VERSION 5.8 ;
BUSBITCHARS "[]" ;
DIVIDERCHAR "/" ;
UNITS
    DATABASE MICRONS 1000 ;
END UNITS

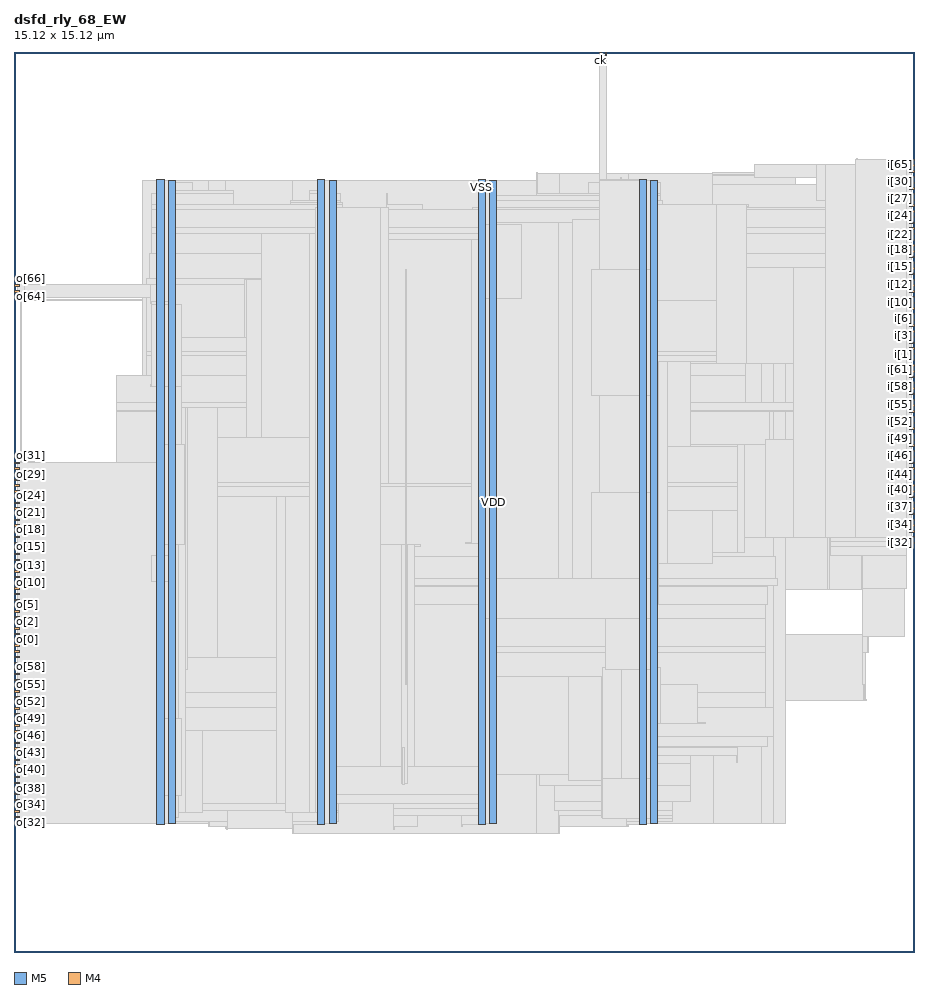
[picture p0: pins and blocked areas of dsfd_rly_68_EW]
MACRO dsfd_rly_68_EW
  FOREIGN dsfd_rly_68_EW 0 0 ;
  CLASS BLOCK ;
  SIZE 15.12 BY 15.12 ;
  PIN ck
    DIRECTION INPUT ;
    USE SIGNAL ;
    PORT
      LAYER M5 ;
        RECT  9.84 15.036 9.864 15.12 ;
    END
  END ck
  PIN i[0]
    DIRECTION INPUT ;
    USE SIGNAL ;
    PORT
      LAYER M4 ;
        RECT  15.036 9.936 15.12 9.96 ;
    END
  END i[0]
  PIN i[10]
    DIRECTION INPUT ;
    USE SIGNAL ;
    PORT
      LAYER M4 ;
        RECT  15.036 10.896 15.12 10.92 ;
    END
  END i[10]
  PIN i[11]
    DIRECTION INPUT ;
    USE SIGNAL ;
    PORT
      LAYER M4 ;
        RECT  15.036 10.992 15.12 11.016 ;
    END
  END i[11]
  PIN i[12]
    DIRECTION INPUT ;
    USE SIGNAL ;
    PORT
      LAYER M4 ;
        RECT  15.036 11.088 15.12 11.112 ;
    END
  END i[12]
  PIN i[13]
    DIRECTION INPUT ;
    USE SIGNAL ;
    PORT
      LAYER M4 ;
        RECT  15.036 11.184 15.12 11.208 ;
    END
  END i[13]
  PIN i[14]
    DIRECTION INPUT ;
    USE SIGNAL ;
    PORT
      LAYER M4 ;
        RECT  15.036 11.28 15.12 11.304 ;
    END
  END i[14]
  PIN i[15]
    DIRECTION INPUT ;
    USE SIGNAL ;
    PORT
      LAYER M4 ;
        RECT  15.036 11.376 15.12 11.4 ;
    END
  END i[15]
  PIN i[16]
    DIRECTION INPUT ;
    USE SIGNAL ;
    PORT
      LAYER M4 ;
        RECT  15.036 11.472 15.12 11.496 ;
    END
  END i[16]
  PIN i[17]
    DIRECTION INPUT ;
    USE SIGNAL ;
    PORT
      LAYER M4 ;
        RECT  15.036 11.568 15.12 11.592 ;
    END
  END i[17]
  PIN i[18]
    DIRECTION INPUT ;
    USE SIGNAL ;
    PORT
      LAYER M4 ;
        RECT  15.036 11.664 15.12 11.688 ;
    END
  END i[18]
  PIN i[19]
    DIRECTION INPUT ;
    USE SIGNAL ;
    PORT
      LAYER M4 ;
        RECT  15.036 11.76 15.12 11.784 ;
    END
  END i[19]
  PIN i[1]
    DIRECTION INPUT ;
    USE SIGNAL ;
    PORT
      LAYER M4 ;
        RECT  15.036 10.032 15.12 10.056 ;
    END
  END i[1]
  PIN i[20]
    DIRECTION INPUT ;
    USE SIGNAL ;
    PORT
      LAYER M4 ;
        RECT  15.036 11.856 15.12 11.88 ;
    END
  END i[20]
  PIN i[21]
    DIRECTION INPUT ;
    USE SIGNAL ;
    PORT
      LAYER M4 ;
        RECT  15.036 11.952 15.12 11.976 ;
    END
  END i[21]
  PIN i[22]
    DIRECTION INPUT ;
    USE SIGNAL ;
    PORT
      LAYER M4 ;
        RECT  15.036 12.048 15.12 12.072 ;
    END
  END i[22]
  PIN i[23]
    DIRECTION INPUT ;
    USE SIGNAL ;
    PORT
      LAYER M4 ;
        RECT  15.036 12.144 15.12 12.168 ;
    END
  END i[23]
  PIN i[24]
    DIRECTION INPUT ;
    USE SIGNAL ;
    PORT
      LAYER M4 ;
        RECT  15.036 12.24 15.12 12.264 ;
    END
  END i[24]
  PIN i[25]
    DIRECTION INPUT ;
    USE SIGNAL ;
    PORT
      LAYER M4 ;
        RECT  15.036 12.336 15.12 12.36 ;
    END
  END i[25]
  PIN i[26]
    DIRECTION INPUT ;
    USE SIGNAL ;
    PORT
      LAYER M4 ;
        RECT  15.036 12.432 15.12 12.456 ;
    END
  END i[26]
  PIN i[27]
    DIRECTION INPUT ;
    USE SIGNAL ;
    PORT
      LAYER M4 ;
        RECT  15.036 12.528 15.12 12.552 ;
    END
  END i[27]
  PIN i[28]
    DIRECTION INPUT ;
    USE SIGNAL ;
    PORT
      LAYER M4 ;
        RECT  15.036 12.624 15.12 12.648 ;
    END
  END i[28]
  PIN i[29]
    DIRECTION INPUT ;
    USE SIGNAL ;
    PORT
      LAYER M4 ;
        RECT  15.036 12.72 15.12 12.744 ;
    END
  END i[29]
  PIN i[2]
    DIRECTION INPUT ;
    USE SIGNAL ;
    PORT
      LAYER M4 ;
        RECT  15.036 10.128 15.12 10.152 ;
    END
  END i[2]
  PIN i[30]
    DIRECTION INPUT ;
    USE SIGNAL ;
    PORT
      LAYER M4 ;
        RECT  15.036 12.816 15.12 12.84 ;
    END
  END i[30]
  PIN i[31]
    DIRECTION INPUT ;
    USE SIGNAL ;
    PORT
      LAYER M4 ;
        RECT  15.036 12.912 15.12 12.936 ;
    END
  END i[31]
  PIN i[32]
    DIRECTION INPUT ;
    USE SIGNAL ;
    PORT
      LAYER M4 ;
        RECT  15.036 6.864 15.12 6.888 ;
    END
  END i[32]
  PIN i[33]
    DIRECTION INPUT ;
    USE SIGNAL ;
    PORT
      LAYER M4 ;
        RECT  15.036 6.96 15.12 6.984 ;
    END
  END i[33]
  PIN i[34]
    DIRECTION INPUT ;
    USE SIGNAL ;
    PORT
      LAYER M4 ;
        RECT  15.036 7.056 15.12 7.08 ;
    END
  END i[34]
  PIN i[35]
    DIRECTION INPUT ;
    USE SIGNAL ;
    PORT
      LAYER M4 ;
        RECT  15.036 7.152 15.12 7.176 ;
    END
  END i[35]
  PIN i[36]
    DIRECTION INPUT ;
    USE SIGNAL ;
    PORT
      LAYER M4 ;
        RECT  15.036 7.248 15.12 7.272 ;
    END
  END i[36]
  PIN i[37]
    DIRECTION INPUT ;
    USE SIGNAL ;
    PORT
      LAYER M4 ;
        RECT  15.036 7.344 15.12 7.368 ;
    END
  END i[37]
  PIN i[38]
    DIRECTION INPUT ;
    USE SIGNAL ;
    PORT
      LAYER M4 ;
        RECT  15.036 7.44 15.12 7.464 ;
    END
  END i[38]
  PIN i[39]
    DIRECTION INPUT ;
    USE SIGNAL ;
    PORT
      LAYER M4 ;
        RECT  15.036 7.536 15.12 7.56 ;
    END
  END i[39]
  PIN i[3]
    DIRECTION INPUT ;
    USE SIGNAL ;
    PORT
      LAYER M4 ;
        RECT  15.036 10.224 15.12 10.248 ;
    END
  END i[3]
  PIN i[40]
    DIRECTION INPUT ;
    USE SIGNAL ;
    PORT
      LAYER M4 ;
        RECT  15.036 7.632 15.12 7.656 ;
    END
  END i[40]
  PIN i[41]
    DIRECTION INPUT ;
    USE SIGNAL ;
    PORT
      LAYER M4 ;
        RECT  15.036 7.728 15.12 7.752 ;
    END
  END i[41]
  PIN i[42]
    DIRECTION INPUT ;
    USE SIGNAL ;
    PORT
      LAYER M4 ;
        RECT  15.036 7.824 15.12 7.848 ;
    END
  END i[42]
  PIN i[43]
    DIRECTION INPUT ;
    USE SIGNAL ;
    PORT
      LAYER M4 ;
        RECT  15.036 7.92 15.12 7.944 ;
    END
  END i[43]
  PIN i[44]
    DIRECTION INPUT ;
    USE SIGNAL ;
    PORT
      LAYER M4 ;
        RECT  15.036 8.016 15.12 8.04 ;
    END
  END i[44]
  PIN i[45]
    DIRECTION INPUT ;
    USE SIGNAL ;
    PORT
      LAYER M4 ;
        RECT  15.036 8.112 15.12 8.136 ;
    END
  END i[45]
  PIN i[46]
    DIRECTION INPUT ;
    USE SIGNAL ;
    PORT
      LAYER M4 ;
        RECT  15.036 8.208 15.12 8.232 ;
    END
  END i[46]
  PIN i[47]
    DIRECTION INPUT ;
    USE SIGNAL ;
    PORT
      LAYER M4 ;
        RECT  15.036 8.304 15.12 8.328 ;
    END
  END i[47]
  PIN i[48]
    DIRECTION INPUT ;
    USE SIGNAL ;
    PORT
      LAYER M4 ;
        RECT  15.036 8.4 15.12 8.424 ;
    END
  END i[48]
  PIN i[49]
    DIRECTION INPUT ;
    USE SIGNAL ;
    PORT
      LAYER M4 ;
        RECT  15.036 8.496 15.12 8.52 ;
    END
  END i[49]
  PIN i[4]
    DIRECTION INPUT ;
    USE SIGNAL ;
    PORT
      LAYER M4 ;
        RECT  15.036 10.32 15.12 10.344 ;
    END
  END i[4]
  PIN i[50]
    DIRECTION INPUT ;
    USE SIGNAL ;
    PORT
      LAYER M4 ;
        RECT  15.036 8.592 15.12 8.616 ;
    END
  END i[50]
  PIN i[51]
    DIRECTION INPUT ;
    USE SIGNAL ;
    PORT
      LAYER M4 ;
        RECT  15.036 8.688 15.12 8.712 ;
    END
  END i[51]
  PIN i[52]
    DIRECTION INPUT ;
    USE SIGNAL ;
    PORT
      LAYER M4 ;
        RECT  15.036 8.784 15.12 8.808 ;
    END
  END i[52]
  PIN i[53]
    DIRECTION INPUT ;
    USE SIGNAL ;
    PORT
      LAYER M4 ;
        RECT  15.036 8.88 15.12 8.904 ;
    END
  END i[53]
  PIN i[54]
    DIRECTION INPUT ;
    USE SIGNAL ;
    PORT
      LAYER M4 ;
        RECT  15.036 8.976 15.12 9 ;
    END
  END i[54]
  PIN i[55]
    DIRECTION INPUT ;
    USE SIGNAL ;
    PORT
      LAYER M4 ;
        RECT  15.036 9.072 15.12 9.096 ;
    END
  END i[55]
  PIN i[56]
    DIRECTION INPUT ;
    USE SIGNAL ;
    PORT
      LAYER M4 ;
        RECT  15.036 9.168 15.12 9.192 ;
    END
  END i[56]
  PIN i[57]
    DIRECTION INPUT ;
    USE SIGNAL ;
    PORT
      LAYER M4 ;
        RECT  15.036 9.264 15.12 9.288 ;
    END
  END i[57]
  PIN i[58]
    DIRECTION INPUT ;
    USE SIGNAL ;
    PORT
      LAYER M4 ;
        RECT  15.036 9.36 15.12 9.384 ;
    END
  END i[58]
  PIN i[59]
    DIRECTION INPUT ;
    USE SIGNAL ;
    PORT
      LAYER M4 ;
        RECT  15.036 9.456 15.12 9.48 ;
    END
  END i[59]
  PIN i[5]
    DIRECTION INPUT ;
    USE SIGNAL ;
    PORT
      LAYER M4 ;
        RECT  15.036 10.416 15.12 10.44 ;
    END
  END i[5]
  PIN i[60]
    DIRECTION INPUT ;
    USE SIGNAL ;
    PORT
      LAYER M4 ;
        RECT  15.036 9.552 15.12 9.576 ;
    END
  END i[60]
  PIN i[61]
    DIRECTION INPUT ;
    USE SIGNAL ;
    PORT
      LAYER M4 ;
        RECT  15.036 9.648 15.12 9.672 ;
    END
  END i[61]
  PIN i[62]
    DIRECTION INPUT ;
    USE SIGNAL ;
    PORT
      LAYER M4 ;
        RECT  15.036 9.744 15.12 9.768 ;
    END
  END i[62]
  PIN i[63]
    DIRECTION INPUT ;
    USE SIGNAL ;
    PORT
      LAYER M4 ;
        RECT  15.036 9.84 15.12 9.864 ;
    END
  END i[63]
  PIN i[64]
    DIRECTION INPUT ;
    USE SIGNAL ;
    PORT
      LAYER M4 ;
        RECT  15.036 13.008 15.12 13.032 ;
    END
  END i[64]
  PIN i[65]
    DIRECTION INPUT ;
    USE SIGNAL ;
    PORT
      LAYER M4 ;
        RECT  15.036 13.104 15.12 13.128 ;
    END
  END i[65]
  PIN i[66]
    DIRECTION INPUT ;
    USE SIGNAL ;
    PORT
      LAYER M4 ;
        RECT  15.036 13.2 15.12 13.224 ;
    END
  END i[66]
  PIN i[67]
    DIRECTION INPUT ;
    USE SIGNAL ;
    PORT
      LAYER M4 ;
        RECT  15.036 13.296 15.12 13.32 ;
    END
  END i[67]
  PIN i[6]
    DIRECTION INPUT ;
    USE SIGNAL ;
    PORT
      LAYER M4 ;
        RECT  15.036 10.512 15.12 10.536 ;
    END
  END i[6]
  PIN i[7]
    DIRECTION INPUT ;
    USE SIGNAL ;
    PORT
      LAYER M4 ;
        RECT  15.036 10.608 15.12 10.632 ;
    END
  END i[7]
  PIN i[8]
    DIRECTION INPUT ;
    USE SIGNAL ;
    PORT
      LAYER M4 ;
        RECT  15.036 10.704 15.12 10.728 ;
    END
  END i[8]
  PIN i[9]
    DIRECTION INPUT ;
    USE SIGNAL ;
    PORT
      LAYER M4 ;
        RECT  15.036 10.8 15.12 10.824 ;
    END
  END i[9]
  PIN o[0]
    DIRECTION OUTPUT ;
    USE SIGNAL ;
    PORT
      LAYER M4 ;
        RECT  0 5.232 0.084 5.256 ;
    END
  END o[0]
  PIN o[10]
    DIRECTION OUTPUT ;
    USE SIGNAL ;
    PORT
      LAYER M4 ;
        RECT  0 6.192 0.084 6.216 ;
    END
  END o[10]
  PIN o[11]
    DIRECTION OUTPUT ;
    USE SIGNAL ;
    PORT
      LAYER M4 ;
        RECT  0 6.288 0.084 6.312 ;
    END
  END o[11]
  PIN o[12]
    DIRECTION OUTPUT ;
    USE SIGNAL ;
    PORT
      LAYER M4 ;
        RECT  0 6.384 0.084 6.408 ;
    END
  END o[12]
  PIN o[13]
    DIRECTION OUTPUT ;
    USE SIGNAL ;
    PORT
      LAYER M4 ;
        RECT  0 6.48 0.084 6.504 ;
    END
  END o[13]
  PIN o[14]
    DIRECTION OUTPUT ;
    USE SIGNAL ;
    PORT
      LAYER M4 ;
        RECT  0 6.576 0.084 6.6 ;
    END
  END o[14]
  PIN o[15]
    DIRECTION OUTPUT ;
    USE SIGNAL ;
    PORT
      LAYER M4 ;
        RECT  0 6.672 0.084 6.696 ;
    END
  END o[15]
  PIN o[16]
    DIRECTION OUTPUT ;
    USE SIGNAL ;
    PORT
      LAYER M4 ;
        RECT  0 6.768 0.084 6.792 ;
    END
  END o[16]
  PIN o[17]
    DIRECTION OUTPUT ;
    USE SIGNAL ;
    PORT
      LAYER M4 ;
        RECT  0 6.864 0.084 6.888 ;
    END
  END o[17]
  PIN o[18]
    DIRECTION OUTPUT ;
    USE SIGNAL ;
    PORT
      LAYER M4 ;
        RECT  0 6.96 0.084 6.984 ;
    END
  END o[18]
  PIN o[19]
    DIRECTION OUTPUT ;
    USE SIGNAL ;
    PORT
      LAYER M4 ;
        RECT  0 7.056 0.084 7.08 ;
    END
  END o[19]
  PIN o[1]
    DIRECTION OUTPUT ;
    USE SIGNAL ;
    PORT
      LAYER M4 ;
        RECT  0 5.328 0.084 5.352 ;
    END
  END o[1]
  PIN o[20]
    DIRECTION OUTPUT ;
    USE SIGNAL ;
    PORT
      LAYER M4 ;
        RECT  0 7.152 0.084 7.176 ;
    END
  END o[20]
  PIN o[21]
    DIRECTION OUTPUT ;
    USE SIGNAL ;
    PORT
      LAYER M4 ;
        RECT  0 7.248 0.084 7.272 ;
    END
  END o[21]
  PIN o[22]
    DIRECTION OUTPUT ;
    USE SIGNAL ;
    PORT
      LAYER M4 ;
        RECT  0 7.344 0.084 7.368 ;
    END
  END o[22]
  PIN o[23]
    DIRECTION OUTPUT ;
    USE SIGNAL ;
    PORT
      LAYER M4 ;
        RECT  0 7.44 0.084 7.464 ;
    END
  END o[23]
  PIN o[24]
    DIRECTION OUTPUT ;
    USE SIGNAL ;
    PORT
      LAYER M4 ;
        RECT  0 7.536 0.084 7.56 ;
    END
  END o[24]
  PIN o[25]
    DIRECTION OUTPUT ;
    USE SIGNAL ;
    PORT
      LAYER M4 ;
        RECT  0 7.632 0.084 7.656 ;
    END
  END o[25]
  PIN o[26]
    DIRECTION OUTPUT ;
    USE SIGNAL ;
    PORT
      LAYER M4 ;
        RECT  0 7.728 0.084 7.752 ;
    END
  END o[26]
  PIN o[27]
    DIRECTION OUTPUT ;
    USE SIGNAL ;
    PORT
      LAYER M4 ;
        RECT  0 7.824 0.084 7.848 ;
    END
  END o[27]
  PIN o[28]
    DIRECTION OUTPUT ;
    USE SIGNAL ;
    PORT
      LAYER M4 ;
        RECT  0 7.92 0.084 7.944 ;
    END
  END o[28]
  PIN o[29]
    DIRECTION OUTPUT ;
    USE SIGNAL ;
    PORT
      LAYER M4 ;
        RECT  0 8.016 0.084 8.04 ;
    END
  END o[29]
  PIN o[2]
    DIRECTION OUTPUT ;
    USE SIGNAL ;
    PORT
      LAYER M4 ;
        RECT  0 5.424 0.084 5.448 ;
    END
  END o[2]
  PIN o[30]
    DIRECTION OUTPUT ;
    USE SIGNAL ;
    PORT
      LAYER M4 ;
        RECT  0 8.112 0.084 8.136 ;
    END
  END o[30]
  PIN o[31]
    DIRECTION OUTPUT ;
    USE SIGNAL ;
    PORT
      LAYER M4 ;
        RECT  0 8.208 0.084 8.232 ;
    END
  END o[31]
  PIN o[32]
    DIRECTION OUTPUT ;
    USE SIGNAL ;
    PORT
      LAYER M4 ;
        RECT  0 2.16 0.084 2.184 ;
    END
  END o[32]
  PIN o[33]
    DIRECTION OUTPUT ;
    USE SIGNAL ;
    PORT
      LAYER M4 ;
        RECT  0 2.256 0.084 2.28 ;
    END
  END o[33]
  PIN o[34]
    DIRECTION OUTPUT ;
    USE SIGNAL ;
    PORT
      LAYER M4 ;
        RECT  0 2.352 0.084 2.376 ;
    END
  END o[34]
  PIN o[35]
    DIRECTION OUTPUT ;
    USE SIGNAL ;
    PORT
      LAYER M4 ;
        RECT  0 2.448 0.084 2.472 ;
    END
  END o[35]
  PIN o[36]
    DIRECTION OUTPUT ;
    USE SIGNAL ;
    PORT
      LAYER M4 ;
        RECT  0 2.544 0.084 2.568 ;
    END
  END o[36]
  PIN o[37]
    DIRECTION OUTPUT ;
    USE SIGNAL ;
    PORT
      LAYER M4 ;
        RECT  0 2.64 0.084 2.664 ;
    END
  END o[37]
  PIN o[38]
    DIRECTION OUTPUT ;
    USE SIGNAL ;
    PORT
      LAYER M4 ;
        RECT  0 2.736 0.084 2.76 ;
    END
  END o[38]
  PIN o[39]
    DIRECTION OUTPUT ;
    USE SIGNAL ;
    PORT
      LAYER M4 ;
        RECT  0 2.832 0.084 2.856 ;
    END
  END o[39]
  PIN o[3]
    DIRECTION OUTPUT ;
    USE SIGNAL ;
    PORT
      LAYER M4 ;
        RECT  0 5.52 0.084 5.544 ;
    END
  END o[3]
  PIN o[40]
    DIRECTION OUTPUT ;
    USE SIGNAL ;
    PORT
      LAYER M4 ;
        RECT  0 2.928 0.084 2.952 ;
    END
  END o[40]
  PIN o[41]
    DIRECTION OUTPUT ;
    USE SIGNAL ;
    PORT
      LAYER M4 ;
        RECT  0 3.024 0.084 3.048 ;
    END
  END o[41]
  PIN o[42]
    DIRECTION OUTPUT ;
    USE SIGNAL ;
    PORT
      LAYER M4 ;
        RECT  0 3.12 0.084 3.144 ;
    END
  END o[42]
  PIN o[43]
    DIRECTION OUTPUT ;
    USE SIGNAL ;
    PORT
      LAYER M4 ;
        RECT  0 3.216 0.084 3.24 ;
    END
  END o[43]
  PIN o[44]
    DIRECTION OUTPUT ;
    USE SIGNAL ;
    PORT
      LAYER M4 ;
        RECT  0 3.312 0.084 3.336 ;
    END
  END o[44]
  PIN o[45]
    DIRECTION OUTPUT ;
    USE SIGNAL ;
    PORT
      LAYER M4 ;
        RECT  0 3.408 0.084 3.432 ;
    END
  END o[45]
  PIN o[46]
    DIRECTION OUTPUT ;
    USE SIGNAL ;
    PORT
      LAYER M4 ;
        RECT  0 3.504 0.084 3.528 ;
    END
  END o[46]
  PIN o[47]
    DIRECTION OUTPUT ;
    USE SIGNAL ;
    PORT
      LAYER M4 ;
        RECT  0 3.6 0.084 3.624 ;
    END
  END o[47]
  PIN o[48]
    DIRECTION OUTPUT ;
    USE SIGNAL ;
    PORT
      LAYER M4 ;
        RECT  0 3.696 0.084 3.72 ;
    END
  END o[48]
  PIN o[49]
    DIRECTION OUTPUT ;
    USE SIGNAL ;
    PORT
      LAYER M4 ;
        RECT  0 3.792 0.084 3.816 ;
    END
  END o[49]
  PIN o[4]
    DIRECTION OUTPUT ;
    USE SIGNAL ;
    PORT
      LAYER M4 ;
        RECT  0 5.616 0.084 5.64 ;
    END
  END o[4]
  PIN o[50]
    DIRECTION OUTPUT ;
    USE SIGNAL ;
    PORT
      LAYER M4 ;
        RECT  0 3.888 0.084 3.912 ;
    END
  END o[50]
  PIN o[51]
    DIRECTION OUTPUT ;
    USE SIGNAL ;
    PORT
      LAYER M4 ;
        RECT  0 3.984 0.084 4.008 ;
    END
  END o[51]
  PIN o[52]
    DIRECTION OUTPUT ;
    USE SIGNAL ;
    PORT
      LAYER M4 ;
        RECT  0 4.08 0.084 4.104 ;
    END
  END o[52]
  PIN o[53]
    DIRECTION OUTPUT ;
    USE SIGNAL ;
    PORT
      LAYER M4 ;
        RECT  0 4.176 0.084 4.2 ;
    END
  END o[53]
  PIN o[54]
    DIRECTION OUTPUT ;
    USE SIGNAL ;
    PORT
      LAYER M4 ;
        RECT  0 4.272 0.084 4.296 ;
    END
  END o[54]
  PIN o[55]
    DIRECTION OUTPUT ;
    USE SIGNAL ;
    PORT
      LAYER M4 ;
        RECT  0 4.368 0.084 4.392 ;
    END
  END o[55]
  PIN o[56]
    DIRECTION OUTPUT ;
    USE SIGNAL ;
    PORT
      LAYER M4 ;
        RECT  0 4.464 0.084 4.488 ;
    END
  END o[56]
  PIN o[57]
    DIRECTION OUTPUT ;
    USE SIGNAL ;
    PORT
      LAYER M4 ;
        RECT  0 4.56 0.084 4.584 ;
    END
  END o[57]
  PIN o[58]
    DIRECTION OUTPUT ;
    USE SIGNAL ;
    PORT
      LAYER M4 ;
        RECT  0 4.656 0.084 4.68 ;
    END
  END o[58]
  PIN o[59]
    DIRECTION OUTPUT ;
    USE SIGNAL ;
    PORT
      LAYER M4 ;
        RECT  0 4.752 0.084 4.776 ;
    END
  END o[59]
  PIN o[5]
    DIRECTION OUTPUT ;
    USE SIGNAL ;
    PORT
      LAYER M4 ;
        RECT  0 5.712 0.084 5.736 ;
    END
  END o[5]
  PIN o[60]
    DIRECTION OUTPUT ;
    USE SIGNAL ;
    PORT
      LAYER M4 ;
        RECT  0 4.848 0.084 4.872 ;
    END
  END o[60]
  PIN o[61]
    DIRECTION OUTPUT ;
    USE SIGNAL ;
    PORT
      LAYER M4 ;
        RECT  0 4.944 0.084 4.968 ;
    END
  END o[61]
  PIN o[62]
    DIRECTION OUTPUT ;
    USE SIGNAL ;
    PORT
      LAYER M4 ;
        RECT  0 5.04 0.084 5.064 ;
    END
  END o[62]
  PIN o[63]
    DIRECTION OUTPUT ;
    USE SIGNAL ;
    PORT
      LAYER M4 ;
        RECT  0 5.136 0.084 5.16 ;
    END
  END o[63]
  PIN o[64]
    DIRECTION OUTPUT ;
    USE SIGNAL ;
    PORT
      LAYER M4 ;
        RECT  0 10.992 0.084 11.016 ;
    END
  END o[64]
  PIN o[65]
    DIRECTION OUTPUT ;
    USE SIGNAL ;
    PORT
      LAYER M4 ;
        RECT  0 11.088 0.084 11.112 ;
    END
  END o[65]
  PIN o[66]
    DIRECTION OUTPUT ;
    USE SIGNAL ;
    PORT
      LAYER M4 ;
        RECT  0 11.184 0.084 11.208 ;
    END
  END o[66]
  PIN o[67]
    DIRECTION OUTPUT ;
    USE SIGNAL ;
    PORT
      LAYER M4 ;
        RECT  0 11.28 0.084 11.304 ;
    END
  END o[67]
  PIN o[6]
    DIRECTION OUTPUT ;
    USE SIGNAL ;
    PORT
      LAYER M4 ;
        RECT  0 5.808 0.084 5.832 ;
    END
  END o[6]
  PIN o[7]
    DIRECTION OUTPUT ;
    USE SIGNAL ;
    PORT
      LAYER M4 ;
        RECT  0 5.904 0.084 5.928 ;
    END
  END o[7]
  PIN o[8]
    DIRECTION OUTPUT ;
    USE SIGNAL ;
    PORT
      LAYER M4 ;
        RECT  0 6 0.084 6.024 ;
    END
  END o[8]
  PIN o[9]
    DIRECTION OUTPUT ;
    USE SIGNAL ;
    PORT
      LAYER M4 ;
        RECT  0 6.096 0.084 6.12 ;
    END
  END o[9]
  PIN rs
    DIRECTION INPUT ;
    USE SIGNAL ;
    PORT
      LAYER M5 ;
        RECT  9.936 15.036 9.96 15.12 ;
    END
  END rs
  PIN VDD
    DIRECTION INOUT ;
    USE POWER ;
    PORT
      LAYER M5 ;
        RECT  10.692 2.151 10.812 12.969 ;
        RECT  7.992 2.151 8.112 12.969 ;
        RECT  5.292 2.151 5.412 12.969 ;
        RECT  2.592 2.151 2.712 12.969 ;
    END
  END VDD
  PIN VSS
    DIRECTION INOUT ;
    USE GROUND ;
    PORT
      LAYER M5 ;
        RECT  10.5 2.137 10.62 12.983 ;
        RECT  7.8 2.137 7.92 12.983 ;
        RECT  5.1 2.137 5.22 12.983 ;
        RECT  2.4 2.137 2.52 12.983 ;
    END
  END VSS
  OBS
    LAYER RVTN ;
     RECT  2.16 2.16 12.96 2.295 ;
     RECT  2.16 2.565 12.96 2.835 ;
     RECT  2.16 3.105 12.96 3.375 ;
     RECT  2.16 3.645 12.96 3.915 ;
     RECT  2.16 4.185 12.96 4.455 ;
     RECT  2.16 4.725 12.96 4.995 ;
     RECT  2.16 5.265 12.96 5.535 ;
     RECT  2.16 5.805 12.96 6.075 ;
     RECT  2.16 6.345 12.96 6.615 ;
     RECT  2.16 6.885 12.96 7.155 ;
     RECT  2.16 7.425 12.96 7.695 ;
     RECT  2.16 7.965 12.96 8.235 ;
     RECT  2.16 8.505 12.96 8.775 ;
     RECT  2.16 9.045 12.96 9.315 ;
     RECT  2.16 9.585 12.96 9.855 ;
     RECT  2.16 10.125 12.96 10.395 ;
     RECT  2.16 10.665 12.96 10.935 ;
     RECT  2.16 11.205 12.96 11.475 ;
     RECT  2.16 11.745 12.96 12.015 ;
     RECT  2.16 12.285 12.96 12.555 ;
     RECT  2.16 12.825 12.96 12.96 ;
    LAYER RVTP ;
     RECT  2.16 2.295 12.96 2.565 ;
     RECT  2.16 2.835 12.96 3.105 ;
     RECT  2.16 3.375 12.96 3.645 ;
     RECT  2.16 3.915 12.96 4.185 ;
     RECT  2.16 4.455 12.96 4.725 ;
     RECT  2.16 4.995 12.96 5.265 ;
     RECT  2.16 5.535 12.96 5.805 ;
     RECT  2.16 6.075 12.96 6.345 ;
     RECT  2.16 6.615 12.96 6.885 ;
     RECT  2.16 7.155 12.96 7.425 ;
     RECT  2.16 7.695 12.96 7.965 ;
     RECT  2.16 8.235 12.96 8.505 ;
     RECT  2.16 8.775 12.96 9.045 ;
     RECT  2.16 9.315 12.96 9.585 ;
     RECT  2.16 9.855 12.96 10.125 ;
     RECT  2.16 10.395 12.96 10.665 ;
     RECT  2.16 10.935 12.96 11.205 ;
     RECT  2.16 11.475 12.96 11.745 ;
     RECT  2.16 12.015 12.96 12.285 ;
     RECT  2.16 12.555 12.96 12.825 ;
    LAYER M1 ;
     RECT  2.16 2.151 12.96 12.969 ;
    LAYER M2 ;
     RECT  0.103 3.276 0.139 3.294 ;
     RECT  0.139 3.276 0.175 3.672 ;
     RECT  0.103 6.786 0.175 7.344 ;
     RECT  0.175 3.114 0.211 3.672 ;
     RECT  0.175 6.156 0.211 7.344 ;
     RECT  0.211 6.156 0.347 7.839 ;
     RECT  0.211 2.574 0.823 3.672 ;
     RECT  0.347 6.156 1.723 7.344 ;
     RECT  1.723 6.12 2.155 7.344 ;
     RECT  0.823 2.574 2.16 4.284 ;
     RECT  2.155 6.012 2.16 7.614 ;
     RECT  1.723 9.666 2.16 9.684 ;
     RECT  0.103 10.944 2.16 10.962 ;
     RECT  2.16 2.151 3.271 12.969 ;
     RECT  3.271 2.106 3.559 12.969 ;
     RECT  3.559 2.07 4.675 12.969 ;
     RECT  4.675 1.998 8.779 12.969 ;
     RECT  8.779 1.998 9.167 13.086 ;
     RECT  9.167 2.106 10.319 13.086 ;
     RECT  10.319 2.151 11.759 13.086 ;
     RECT  11.759 2.151 12.551 13.05 ;
     RECT  12.551 2.151 12.767 13.014 ;
     RECT  12.767 2.151 12.96 12.969 ;
     RECT  12.96 6.084 13.667 12.888 ;
     RECT  13.667 6.084 13.703 12.816 ;
     RECT  13.703 6.084 14.243 7.146 ;
     RECT  13.703 8.046 14.243 12.816 ;
     RECT  12.96 4.23 14.279 5.328 ;
     RECT  14.243 12.798 14.279 12.816 ;
     RECT  14.279 4.23 14.315 4.248 ;
     RECT  14.243 8.046 14.315 9.882 ;
     RECT  14.279 5.04 14.351 5.328 ;
     RECT  14.315 8.046 14.351 8.532 ;
     RECT  14.315 9.36 14.387 9.882 ;
     RECT  14.243 6.084 14.927 6.84 ;
     RECT  14.351 5.31 14.963 5.328 ;
     RECT  14.927 6.12 14.999 6.84 ;
     RECT  14.351 8.478 14.999 8.532 ;
     RECT  14.387 9.63 14.999 9.882 ;
     RECT  14.999 6.822 15.035 6.84 ;
     RECT  14.999 8.514 15.035 8.532 ;
     RECT  14.999 9.63 15.035 9.648 ;
     RECT  14.243 10.836 15.035 11.97 ;
    LAYER M3 ;
     RECT  3.564 2.065 3.582 2.101 ;
     RECT  6.372 2.065 6.39 2.101 ;
     RECT  4.68 1.993 4.698 2.143 ;
     RECT  7.524 2.101 7.542 2.143 ;
     RECT  10.296 2.101 10.314 2.143 ;
     RECT  2.415 2.143 2.505 2.155 ;
     RECT  2.304 2.155 2.505 2.191 ;
     RECT  3.276 2.101 3.582 2.191 ;
     RECT  4.68 2.143 5.205 2.191 ;
     RECT  10.296 2.143 10.605 2.191 ;
     RECT  10.296 2.191 11.07 2.251 ;
     RECT  6.372 2.101 6.786 2.299 ;
     RECT  7.524 2.143 7.905 2.299 ;
     RECT  9.144 1.993 9.162 2.299 ;
     RECT  9.9 2.251 11.07 2.299 ;
     RECT  4.68 2.191 5.454 2.347 ;
     RECT  2.304 2.191 3.582 2.371 ;
     RECT  4.572 2.347 5.454 2.371 ;
     RECT  9.144 2.299 11.07 2.371 ;
     RECT  6.372 2.299 7.905 2.413 ;
     RECT  2.304 2.371 5.454 2.497 ;
     RECT  6.372 2.413 8.097 2.497 ;
     RECT  9.072 2.371 11.07 2.533 ;
     RECT  1.26 2.443 1.278 2.539 ;
     RECT  1.152 2.539 1.278 2.573 ;
     RECT  0.216 2.569 0.234 2.635 ;
     RECT  1.152 2.573 1.17 2.635 ;
     RECT  2.304 2.497 8.097 2.641 ;
     RECT  9.072 2.533 11.358 2.803 ;
     RECT  0.216 2.635 1.17 2.813 ;
     RECT  0.216 2.813 0.846 2.923 ;
     RECT  2.268 2.641 8.097 3.163 ;
     RECT  8.82 2.803 11.358 3.163 ;
     RECT  0.144 2.923 0.846 3.271 ;
     RECT  2.268 3.163 11.358 3.307 ;
     RECT  12.132 3.181 12.15 3.307 ;
     RECT  2.268 3.307 12.15 3.443 ;
     RECT  2.304 3.443 12.15 3.451 ;
     RECT  2.304 3.451 12.654 3.613 ;
     RECT  0.108 3.271 0.846 3.629 ;
     RECT  0.144 3.629 0.846 3.649 ;
     RECT  0.144 3.649 1.17 3.749 ;
     RECT  0.144 3.749 0.846 4.109 ;
     RECT  2.304 3.613 12.762 4.109 ;
     RECT  0.828 4.109 0.846 4.289 ;
     RECT  2.304 4.109 12.618 4.363 ;
     RECT  14.292 4.225 14.31 4.495 ;
     RECT  2.268 4.363 12.618 5.035 ;
     RECT  14.256 4.495 14.31 5.035 ;
     RECT  1.728 5.035 12.618 5.131 ;
     RECT  14.256 5.035 14.346 5.305 ;
     RECT  0.144 5.323 0.162 5.501 ;
     RECT  1.152 5.131 12.618 5.597 ;
     RECT  1.728 5.597 12.618 5.845 ;
     RECT  14.256 5.305 14.958 6.115 ;
     RECT  1.728 5.845 12.654 6.143 ;
     RECT  1.764 6.143 12.654 6.151 ;
     RECT  1.764 6.151 12.834 6.269 ;
     RECT  0.18 6.151 0.198 6.331 ;
     RECT  1.764 6.269 12.798 6.647 ;
     RECT  14.256 6.115 14.994 6.655 ;
     RECT  0.144 6.331 0.198 6.781 ;
     RECT  13.716 6.655 14.994 6.817 ;
     RECT  13.716 6.817 15.03 6.893 ;
     RECT  13.716 6.893 14.994 7.195 ;
     RECT  0.108 6.781 0.198 7.469 ;
     RECT  0.144 7.469 0.198 7.627 ;
     RECT  13.68 7.195 14.994 7.627 ;
     RECT  13.644 7.627 14.994 7.799 ;
     RECT  1.764 6.647 12.762 7.819 ;
     RECT  1.728 7.819 12.762 7.889 ;
     RECT  0.144 7.627 0.342 8.203 ;
     RECT  0.108 8.203 0.342 8.237 ;
     RECT  13.68 7.799 14.994 8.509 ;
     RECT  13.68 8.509 15.03 8.815 ;
     RECT  1.728 7.889 12.69 9.085 ;
     RECT  13.644 8.815 15.03 9.085 ;
     RECT  1.728 9.085 15.03 9.101 ;
     RECT  1.728 9.101 13.122 9.239 ;
     RECT  1.728 9.239 12.294 9.689 ;
     RECT  2.232 9.689 12.294 10.021 ;
     RECT  13.104 9.239 13.122 10.021 ;
     RECT  2.232 10.021 13.122 10.093 ;
     RECT  14.22 9.101 15.03 10.093 ;
     RECT  0.108 8.237 0.126 10.967 ;
     RECT  0.144 11.131 0.162 11.309 ;
     RECT  2.232 10.093 15.03 11.309 ;
     RECT  2.268 11.309 15.03 11.741 ;
     RECT  2.304 11.741 15.03 12.077 ;
     RECT  2.304 12.077 14.346 12.173 ;
     RECT  2.304 12.173 14.274 12.479 ;
     RECT  7.704 12.479 14.274 12.515 ;
     RECT  2.304 12.479 5.526 12.551 ;
     RECT  6.264 12.479 6.858 12.551 ;
     RECT  4.644 12.551 5.526 12.587 ;
     RECT  4.644 12.587 5.49 12.623 ;
     RECT  7.815 12.515 10.89 12.623 ;
     RECT  7.815 12.623 10.854 12.707 ;
     RECT  2.304 12.551 3.69 12.749 ;
     RECT  4.968 12.623 5.49 12.749 ;
     RECT  6.264 12.551 6.282 12.749 ;
     RECT  8.784 12.707 10.854 12.749 ;
     RECT  2.415 12.749 3.69 12.785 ;
     RECT  4.968 12.749 5.205 12.785 ;
     RECT  11.736 12.515 14.274 12.893 ;
     RECT  2.415 12.785 3.006 12.929 ;
     RECT  9.648 12.749 10.854 12.929 ;
     RECT  9.9 12.929 10.605 12.941 ;
     RECT  2.415 12.929 2.505 12.977 ;
     RECT  5.115 12.785 5.205 12.977 ;
     RECT  7.815 12.707 7.905 12.977 ;
     RECT  10.188 12.941 10.605 12.977 ;
     RECT  10.188 12.977 10.206 13.019 ;
     RECT  11.736 12.893 13.122 13.037 ;
     RECT  11.736 13.037 12.546 13.055 ;
     RECT  8.784 12.749 8.802 13.091 ;
     RECT  11.736 13.055 12.474 13.091 ;
     RECT  14.148 12.893 14.274 13.133 ;
     RECT  12.456 13.091 12.474 13.229 ;
     RECT  14.148 13.133 14.166 13.325 ;
    LAYER M4 ;
     RECT  0.06 10.992 0.173 11.304 ;
     RECT  0.173 10.992 2.293 11.208 ;
     RECT  0.06 2.16 2.408 8.232 ;
     RECT  2.293 9.504 2.408 9.528 ;
     RECT  2.293 10.896 2.408 11.208 ;
     RECT  2.408 2.148 2.512 12.972 ;
     RECT  2.512 2.256 2.704 12.702 ;
     RECT  2.704 2.256 2.765 9.144 ;
     RECT  2.765 2.352 2.873 9.144 ;
     RECT  2.873 4.752 2.909 9.144 ;
     RECT  2.873 2.352 3.161 3.72 ;
     RECT  2.909 4.944 3.413 9.144 ;
     RECT  2.704 10.32 3.877 11.208 ;
     RECT  3.413 8.64 3.913 9.144 ;
     RECT  3.877 10.32 3.913 11.304 ;
     RECT  3.913 8.64 4.165 11.304 ;
     RECT  3.161 2.496 4.417 3.72 ;
     RECT  3.413 4.944 4.417 7.656 ;
     RECT  4.417 2.496 4.561 7.656 ;
     RECT  4.561 2.352 4.957 7.656 ;
     RECT  4.165 8.64 4.957 12.072 ;
     RECT  4.957 2.352 5.065 12.072 ;
     RECT  5.065 2.352 5.108 12.504 ;
     RECT  5.108 2.148 5.212 12.972 ;
     RECT  5.212 2.418 5.404 12.702 ;
     RECT  5.404 3.12 6.149 12.504 ;
     RECT  6.149 7.872 6.293 12.504 ;
     RECT  6.149 3.12 6.517 6.84 ;
     RECT  6.517 2.832 6.604 6.84 ;
     RECT  6.604 3.12 6.725 6.84 ;
     RECT  6.725 6.816 6.833 6.84 ;
     RECT  7.585 6.864 7.693 6.888 ;
     RECT  6.293 7.872 7.693 11.976 ;
     RECT  6.725 3.12 7.808 5.832 ;
     RECT  7.693 6.864 7.808 11.976 ;
     RECT  7.808 2.148 7.912 12.972 ;
     RECT  7.912 2.418 8.104 12.702 ;
     RECT  8.104 5.616 9.148 12.264 ;
     RECT  8.104 2.976 9.313 4.632 ;
     RECT  9.148 5.76 9.385 12.264 ;
     RECT  9.313 2.88 9.877 4.632 ;
     RECT  9.877 2.256 9.884 4.632 ;
     RECT  9.385 5.76 9.884 12.312 ;
     RECT  9.884 2.256 10.213 4.776 ;
     RECT  9.884 5.76 10.213 12.936 ;
     RECT  10.213 2.256 10.508 12.936 ;
     RECT  10.508 2.148 10.612 12.972 ;
     RECT  10.612 2.418 10.804 12.702 ;
     RECT  10.804 5.856 10.829 9.912 ;
     RECT  10.804 3.84 10.865 4.776 ;
     RECT  10.829 6.528 10.973 9.912 ;
     RECT  10.973 8.496 11.369 9.912 ;
     RECT  10.865 3.84 11.477 4.488 ;
     RECT  11.477 3.84 11.621 3.864 ;
     RECT  10.973 6.528 11.729 7.416 ;
     RECT  11.369 9.888 11.797 9.912 ;
     RECT  10.804 10.944 11.797 12.552 ;
     RECT  11.729 6.72 12.157 7.416 ;
     RECT  11.369 8.496 12.157 8.52 ;
     RECT  12.157 6.72 12.269 8.52 ;
     RECT  11.797 9.888 12.305 12.552 ;
     RECT  12.305 12.528 12.341 12.552 ;
     RECT  12.269 6.96 12.625 8.52 ;
     RECT  12.625 6.96 13.093 8.616 ;
     RECT  12.305 9.888 13.093 11.496 ;
     RECT  12.445 13.008 13.489 13.224 ;
     RECT  13.093 6.96 13.633 11.496 ;
     RECT  13.489 12.624 13.633 13.224 ;
     RECT  13.633 6.96 14.137 13.224 ;
     RECT  14.137 6.96 15.001 13.32 ;
     RECT  15.001 6.864 15.084 13.32 ;
    LAYER M5 ;
     RECT  2.4 2.137 2.52 2.151 ;
     RECT  5.1 2.137 5.22 2.151 ;
     RECT  7.8 2.137 7.92 2.151 ;
     RECT  10.5 2.137 10.62 2.151 ;
     RECT  10.5 2.151 10.812 2.245 ;
     RECT  2.4 2.151 2.712 2.629 ;
     RECT  9.888 2.245 10.812 2.915 ;
     RECT  6.528 2.821 6.552 3.443 ;
     RECT  2.4 2.629 2.808 3.923 ;
     RECT  10.5 2.915 10.812 4.741 ;
     RECT  7.8 2.151 8.112 5.605 ;
     RECT  9.936 4.741 10.812 5.605 ;
     RECT  2.4 3.923 2.712 6.229 ;
     RECT  7.8 5.605 10.812 6.275 ;
     RECT  2.304 6.229 2.712 6.659 ;
     RECT  2.4 6.659 2.712 6.853 ;
     RECT  9.696 6.275 10.812 7.715 ;
     RECT  2.4 6.853 2.856 8.531 ;
     RECT  9.84 7.715 10.812 9.349 ;
     RECT  2.4 8.531 2.808 9.493 ;
     RECT  2.304 9.493 2.808 10.883 ;
     RECT  2.304 10.883 2.712 10.931 ;
     RECT  7.8 6.275 8.112 10.981 ;
     RECT  6.576 4.501 6.6 11.459 ;
     RECT  9.696 9.349 10.812 11.459 ;
     RECT  7.8 10.981 8.52 12.227 ;
     RECT  2.4 10.931 2.712 12.969 ;
     RECT  5.1 2.151 5.412 12.969 ;
     RECT  7.8 12.227 8.112 12.969 ;
     RECT  9.84 11.459 10.812 12.969 ;
     RECT  2.4 12.969 2.52 12.983 ;
     RECT  5.1 12.969 5.22 12.983 ;
     RECT  7.8 12.969 7.92 12.983 ;
     RECT  9.84 12.969 10.62 12.983 ;
     RECT  9.84 12.983 9.96 15.056 ;
  END
END dsfd_rly_68_EW
END LIBRARY
